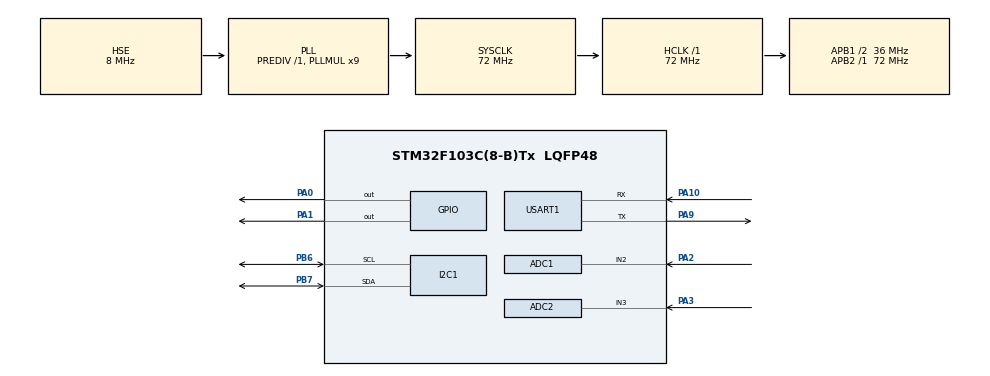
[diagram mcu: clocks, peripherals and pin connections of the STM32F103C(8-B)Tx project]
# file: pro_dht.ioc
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ADC1.Channel-0\#ChannelRegularConversion=ADC_CHANNEL_2
ADC1.NbrOfConversionFlag=1
ADC1.Rank-0\#ChannelRegularConversion=1
ADC1.SamplingTime-0\#ChannelRegularConversion=ADC_SAMPLETIME_55CYCLES_5
ADC1.master=1
ADC2.Channel-0\#ChannelRegularConversion=ADC_CHANNEL_3
ADC2.NbrOfConversionFlag=1
ADC2.Rank-0\#ChannelRegularConversion=1
ADC2.SamplingTime-0\#ChannelRegularConversion=ADC_SAMPLETIME_55CYCLES_5
FREERTOS.Queues01=myQueue01,16,uint16_t,0,Dynamic,NULL,NULL;myQueue02,16,uint16_t,0,Dynamic,NULL,NULL;myQueue03,16,uint16_t,0,Dynamic,NULL,NULL;myQueue04,16,uint16_t,0,Dynamic,NULL,NULL;myQueue05,16,uint16_t,0,Dynamic,NULL,NULL;myQueue06,16,uint16_t,0,Dynamic,NULL,NULL
FREERTOS.Tasks01=defaultTask,0,128,StartDefaultTask,Default,NULL,Dynamic,NULL,NULL;DHT11,0,128,DHT11_FULL,Default,NULL,Dynamic,NULL,NULL;Anh_Sang,0,128,Anh_Sang_FULL,Default,NULL,Dynamic,NULL,NULL
Mcu.Family=STM32F1
Mcu.Name=STM32F103C(8-B)Tx
Mcu.Package=LQFP48
NVIC.PriorityGroup=NVIC_PRIORITYGROUP_4
NVIC.USART1_IRQn=true\:5\:0\:false\:false\:true\:true\:true\:true\:true
PA0-WKUP.Signal=GPIO_Output
PA1.Signal=GPIO_Output
PA10.Mode=Asynchronous
PA10.Signal=USART1_RX
PA13.Mode=Serial_Wire
PA13.Signal=SYS_JTMS-SWDIO
PA14.Mode=Serial_Wire
PA14.Signal=SYS_JTCK-SWCLK
PA2.Signal=ADCx_IN2
PA3.Signal=ADCx_IN3
PA9.Mode=Asynchronous
PA9.Signal=USART1_TX
PB6.GPIO_Speed=GPIO_SPEED_FREQ_HIGH
PB6.Mode=I2C
PB6.Signal=I2C1_SCL
PB7.GPIO_Speed=GPIO_SPEED_FREQ_HIGH
PB7.Mode=I2C
PB7.Signal=I2C1_SDA
PD0-OSC_IN.Mode=HSE-External-Oscillator
PD0-OSC_IN.Signal=RCC_OSC_IN
PD1-OSC_OUT.Mode=HSE-External-Oscillator
PD1-OSC_OUT.Signal=RCC_OSC_OUT
ProjectManager.HeapSize=0x200
ProjectManager.StackSize=0x400
ProjectManager.TargetToolchain=MDK-ARM V5
RCC.ADCPresc=RCC_ADCPCLK2_DIV6
RCC.AHBFreq_Value=72000000
RCC.APB1CLKDivider=RCC_HCLK_DIV2
RCC.APB1Freq_Value=36000000
RCC.APB1TimFreq_Value=72000000
RCC.APB2Freq_Value=72000000
RCC.APB2TimFreq_Value=72000000
RCC.HCLKFreq_Value=72000000
RCC.PLLMUL=RCC_PLL_MUL9
RCC.PLLSourceVirtual=RCC_PLLSOURCE_HSE
RCC.SYSCLKFreq_VALUE=72000000
RCC.SYSCLKSource=RCC_SYSCLKSOURCE_PLLCLK
RCC.USBFreq_Value=72000000
SH.ADCx_IN2.0=ADC1_IN2,IN2
SH.ADCx_IN3.0=ADC2_IN3,IN3
TIM4.Period=0xffff-1
TIM4.Prescaler=72-1
USART1.VirtualMode=VM_ASYNC
VP_FREERTOS_VS_CMSIS_V1.Mode=CMSIS_V1
VP_TIM4_VS_ClockSourceINT.Mode=Internal
board=custom

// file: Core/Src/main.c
/* USER CODE BEGIN Header */
/**
  ******************************************************************************
  * @file           : main.c
  * @brief          : Main program body
  ******************************************************************************
  * @attention
  *
  * <h2><center>&copy; Copyright (c) 2021 STMicroelectronics.
  * All rights reserved.</center></h2>
  *
  * This software component is licensed by ST under BSD 3-Clause license,
  * the "License"; You may not use this file except in compliance with the
  * License. You may obtain a copy of the License at:
  *                        opensource.org/licenses/BSD-3-Clause
  *
  ******************************************************************************
  */
/* USER CODE END Header */
#include "main.h"
#include "cmsis_os.h"

/* USER CODE BEGIN Includes */

#include "i2c-lcd.h"
#include "stdio.h"
#include <string.h>
#include <stdlib.h>
/* USER CODE END Includes */

ADC_HandleTypeDef hadc1;
ADC_HandleTypeDef hadc2;

I2C_HandleTypeDef hi2c1;

TIM_HandleTypeDef htim4;

UART_HandleTypeDef huart1;

osThreadId defaultTaskHandle;
osThreadId DHT11Handle;
osThreadId Anh_SangHandle;
osThreadId LCDHandle;
/* USER CODE BEGIN PV */
osMessageQId myQueue01Handle;
osMessageQId myQueue02Handle;
osMessageQId myQueue03Handle;
osMessageQId myQueue04Handle;
osMessageQId myQueue05Handle;
osMessageQId myQueue06Handle;
/* USER CODE END PV */

void SystemClock_Config(void);
static void MX_GPIO_Init(void);
static void MX_I2C1_Init(void);
static void MX_TIM4_Init(void);
static void MX_ADC1_Init(void);
static void MX_ADC2_Init(void);
static void MX_USART1_UART_Init(void);
void StartDefaultTask(void const * argument);
void DHT11_FULL(void const * argument);
void Anh_Sang_FULL(void const * argument);
void LCD_FULL(void const * argument);
/* USER CODE BEGIN PFP */
uint32_t adc1_value = 0;
uint32_t adc2_value = 0;
#define MAX_BUFFER_SIZE 1024
/* USER CODE END PFP */

/* USER CODE BEGIN 0 */

//delay function in microseconds
void delay (uint16_t time)
{
	__HAL_TIM_SET_COUNTER(&htim4, 0);
	while ((__HAL_TIM_GET_COUNTER(&htim4))<time);
}

/*
//Finction to display temperature
void Display_Temp (int Temp)
{
	char str[20] = {0};
	lcd_put_cur(0,0);

	sprintf (str, "Temp:%d", Temp);
	lcd_send_string(str);
	lcd_send_data('C');
}

////function to display RH
void Display_Rh (int Rh)
{
	char str[20] = {0};
	lcd_put_cur(0,10);

	sprintf (str, "Rh:%d", Rh);
	lcd_send_string(str);
	lcd_send_data('%');
}
*/
//variables declarations
uint8_t Rh_byte1, Rh_byte2, Temp_byte1, Temp_byte2;
uint16_t SUM, RH, TEMP;

uint32_t Temperature = 0;
uint32_t Humidity = 0;
uint8_t Presence = 0;

//function to set the pins as outputs
void Set_Pin_Output(GPIO_TypeDef *GPIOx, uint16_t GPIO_Pin)
{
	GPIO_InitTypeDef GPIO_InitStruct = {0};
	GPIO_InitStruct.Pin = GPIO_Pin;
	GPIO_InitStruct.Mode = GPIO_MODE_OUTPUT_PP;
	GPIO_InitStruct.Speed = GPIO_SPEED_FREQ_LOW;
	HAL_GPIO_Init(GPIOx, &GPIO_InitStruct);
}

//function to set pin as input
void Set_Pin_Input(GPIO_TypeDef *GPIOx, uint16_t GPIO_Pin)
{
	GPIO_InitTypeDef GPIO_InitStruct = {0};
	GPIO_InitStruct.Pin = GPIO_Pin;
	GPIO_InitStruct.Mode = GPIO_MODE_INPUT;
	GPIO_InitStruct.Pull = GPIO_NOPULL; //can be changed to PULLUP if no data is received from the pin
	HAL_GPIO_Init(GPIOx, &GPIO_InitStruct);
}

/***************************DHT11 FUNCTIONS BEGIN HERE**********************************************/
//Define the pin and the port for DHT11 Sensor
#define DHT11_PORT GPIOA
#define DHT11_PIN GPIO_PIN_1

//Function to send the start signal
void DHT11_Start (void)
{
	Set_Pin_Output (DHT11_PORT, DHT11_PIN); //set the dht pin as output
	/***********************************************/
	HAL_GPIO_WritePin(DHT11_PORT, DHT11_PIN, 1); //initialize with data pin high
	HAL_Delay(1000); //wait for 1000 milliseconds
	/***********************************************/

	HAL_GPIO_WritePin (DHT11_PORT, DHT11_PIN, 0); //pull the pin low
	delay(18000); //wait 18 milliseconds
	HAL_GPIO_WritePin (DHT11_PORT, DHT11_PIN, 1); //pull the pin high
	delay(20); //wait for 20 microseconds
	Set_Pin_Input(DHT11_PORT, DHT11_PIN); //set the pin as input
}

//dh11 function to check response
uint8_t DHT11_Check_Response (void)
{
	uint8_t Response = 0;
	delay(40); //first wait for 40 microseconds
	if (!(HAL_GPIO_ReadPin (DHT11_PORT, DHT11_PIN))) //check for pin to be low
	{
		delay(80); //wait for 80 microseconds
		if((HAL_GPIO_ReadPin (DHT11_PORT, DHT11_PIN))) Response = 1; //check if pin is high and return 1 to show sensor is present
		else Response = -1; //255
	}
	while ((HAL_GPIO_ReadPin (DHT11_PORT, DHT11_PIN))); //wait for the pin to go low again

	return Response;
}

//function to read data from dht11 signal pin
uint8_t DHT11_Read (void)
{
	uint8_t i, j;
	for (j=0;j<8;j++)
	{
		while(!(HAL_GPIO_ReadPin (DHT11_PORT, DHT11_PIN))); //wait for the pin to change to high
		delay(40); //wait for 40 microseconds
		if (!(HAL_GPIO_ReadPin (DHT11_PORT, DHT11_PIN))) //if the pin is low
		{
			i&= ~(1<<(7-j)); //write 0
		}
		else i|= (1<<(7-j)); //if the pin is high write 1
		while ((HAL_GPIO_ReadPin (DHT11_PORT, DHT11_PIN))); //wait for the pin to go low
	}

	return i;
}
//////////////////////////////////////DHT0///////////////////////
/* USER CODE END 0
void Display_Temp5 (int Temp5)
{
	char str[20] = {0};
	lcd_put_cur(1,0);

	sprintf (str, "Temp:%d", Temp5);
	lcd_send_string(str);
	lcd_send_data('C');
}

//function to display RH
void Display_Rh5 (int Rh5)
{
	char str[20] = {0};
	lcd_put_cur(1,10);

	sprintf (str, "Rh:%d", Rh5);
	lcd_send_string(str);
	lcd_send_data('%');
}
*/
//variables declarations
uint8_t Rh5_byte1, Rh5_byte2, Temp5_byte1, Temp5_byte2;
uint16_t SUM5, RH5, TEMP5;

uint32_t Temperature5 = 0;
uint32_t Humidity5 = 0;
uint8_t Presence5 = 0;

//function to set the pins as outputs
void Set_Pin_Output5(GPIO_TypeDef *GPIOx, uint16_t GPIO_Pin)
{
	GPIO_InitTypeDef GPIO_InitStruct = {0};
	GPIO_InitStruct.Pin = GPIO_Pin;
	GPIO_InitStruct.Mode = GPIO_MODE_OUTPUT_PP;
	GPIO_InitStruct.Speed = GPIO_SPEED_FREQ_LOW;
	HAL_GPIO_Init(GPIOx, &GPIO_InitStruct);
}

//function to set pin as input
void Set_Pin_Input5(GPIO_TypeDef *GPIOx, uint16_t GPIO_Pin)
{
	GPIO_InitTypeDef GPIO_InitStruct = {0};
	GPIO_InitStruct.Pin = GPIO_Pin;
	GPIO_InitStruct.Mode = GPIO_MODE_INPUT;
	GPIO_InitStruct.Pull = GPIO_NOPULL; //can be changed to PULLUP if no data is received from the pin
	HAL_GPIO_Init(GPIOx, &GPIO_InitStruct);
}

/***************************DHT11 FUNCTIONS BEGIN HERE**********************************************/
//Define the pin and the port for DHT11 Sensor
#define DHT11_PORT GPIOA
#define DHT11_PIN5 GPIO_PIN_0

//Function to send the start signal
void DHT11_Start5 (void)
{
	Set_Pin_Output5 (DHT11_PORT, DHT11_PIN5); //set the dht pin as output
	/***********************************************/
	HAL_GPIO_WritePin(DHT11_PORT, DHT11_PIN5, 1); //initialize with data pin high
	HAL_Delay(1000); //wait for 1000 milliseconds
	/***********************************************/

	HAL_GPIO_WritePin (DHT11_PORT, DHT11_PIN5, 0); //pull the pin low
	delay(18000); //wait 18 milliseconds
	HAL_GPIO_WritePin (DHT11_PORT, DHT11_PIN5, 1); //pull the pin high
	delay(20); //wait for 20 microseconds
	Set_Pin_Input5(DHT11_PORT, DHT11_PIN5); //set the pin as input
}

//dh11 function to check response
uint8_t DHT11_Check_Response5 (void)
{
	uint8_t Response5 = 0;
	delay(40); //first wait for 40 microseconds
	if (!(HAL_GPIO_ReadPin (DHT11_PORT, DHT11_PIN5))) //check for pin to be low
	{
		delay(80); //wait for 80 microseconds
		if((HAL_GPIO_ReadPin (DHT11_PORT, DHT11_PIN5))) Response5 = 1; //check if pin is high and return 1 to show sensor is present
		else Response5 = -1; //255
	}
	while ((HAL_GPIO_ReadPin (DHT11_PORT, DHT11_PIN5))); //wait for the pin to go low again

	return Response5;
}

//function to read data from dht11 signal pin
uint8_t DHT11_Read5 (void)
{
	uint8_t i, j;
	for (j=0;j<8;j++)
	{
		while(!(HAL_GPIO_ReadPin (DHT11_PORT, DHT11_PIN5))); //wait for the pin to change to high
		delay(40); //wait for 40 microseconds
		if (!(HAL_GPIO_ReadPin (DHT11_PORT, DHT11_PIN5))) //if the pin is low
		{
			i&= ~(1<<(7-j)); //write 0
		}
		else i|= (1<<(7-j)); //if the pin is high write 1
		while ((HAL_GPIO_ReadPin (DHT11_PORT, DHT11_PIN5))); //wait for the pin to go low
	}

	return i;
}
////////////
char rxBuffer[3];
void HAL_UART_RxCpltCallback(UART_HandleTypeDef *huart)
{

  if(huart->Instance==USART1)
  {
    if(strcmp(rxBuffer, "O1") == 0)
    {
      HAL_GPIO_WritePin(GPIOA, GPIO_PIN_6, 1); // Turn on LED1
    }
    else if(strcmp(rxBuffer, "X1") == 0)
    {
      HAL_GPIO_WritePin(GPIOA, GPIO_PIN_6, 0); // Turn off LED1
    }
    if(strcmp(rxBuffer, "O2") == 0)
    {
      HAL_GPIO_WritePin(GPIOA, GPIO_PIN_7, 1); // Turn on LED2
    }
    else if(strcmp(rxBuffer, "X2") == 0)
    {
      HAL_GPIO_WritePin(GPIOA, GPIO_PIN_7, 0); // Turn off LED2
    }
    if(strcmp(rxBuffer, "O3") == 0)
    {
      HAL_GPIO_WritePin(GPIOA, GPIO_PIN_8, 1); // Turn on LED3
    }
    else if(strcmp(rxBuffer, "X3") == 0)
    {
      HAL_GPIO_WritePin(GPIOA, GPIO_PIN_8, 0); // Turn off LED3
    }
    HAL_UART_Receive_IT(&huart1, (uint8_t *)rxBuffer, 2); // Enable interrupt receive again
  }
}

int main(void)
{

  /* MCU Configuration--------------------------------------------------------*/

  /* Reset of all peripherals, Initializes the Flash interface and the Systick. */
  HAL_Init();

  /* Configure the system clock */
  SystemClock_Config();

  /* Initialize all configured peripherals */
  MX_GPIO_Init();
  MX_I2C1_Init();
  MX_TIM4_Init();
  MX_ADC1_Init();
  MX_ADC2_Init();
	MX_USART1_UART_Init();
  /* USER CODE BEGIN 2 */
//	HAL_UART_Receive_IT(&huart1, (uint8_t *)rxBuffer, 2);
	HAL_TIM_Base_Start(&htim4);

	lcd_init(); //initialize lcd
	lcd_send_string("INITIALIZING.."); //display string on lcd
	HAL_Delay(2000); //wait for 2 seconds
	lcd_clear(); //clear lcd display

  /* USER CODE END 2 */

	osMessageQDef(myQueue01, 16, uint16_t);
  myQueue01Handle = osMessageCreate(osMessageQ(myQueue01), NULL);

  /* definition and creation of myQueue02 */
  osMessageQDef(myQueue02, 16, uint16_t);
  myQueue02Handle = osMessageCreate(osMessageQ(myQueue02), NULL);

  /* definition and creation of myQueue03 */
  osMessageQDef(myQueue03, 16, uint16_t);
  myQueue03Handle = osMessageCreate(osMessageQ(myQueue03), NULL);

  /* definition and creation of myQueue04 */
  osMessageQDef(myQueue04, 16, uint16_t);
  myQueue04Handle = osMessageCreate(osMessageQ(myQueue04), NULL);
	/* definition and creation of myQueue05 */
  osMessageQDef(myQueue05, 16, uint16_t);
  myQueue05Handle = osMessageCreate(osMessageQ(myQueue05), NULL);

  /* definition and creation of myQueue06 */
  osMessageQDef(myQueue06, 16, uint16_t);
  myQueue06Handle = osMessageCreate(osMessageQ(myQueue06), NULL);
  /* Create the thread(s) */
  /* definition and creation of defaultTask */
  osThreadDef(defaultTask, StartDefaultTask, osPriorityNormal, 0, 128);
  defaultTaskHandle = osThreadCreate(osThread(defaultTask), NULL);

  /* definition and creation of DHT11 */
  osThreadDef(DHT11, DHT11_FULL, osPriorityNormal, 0, 128);
  DHT11Handle = osThreadCreate(osThread(DHT11), NULL);
	/* definition and creation of Anh_Sang */
  osThreadDef(Anh_Sang, Anh_Sang_FULL, osPriorityNormal, 0, 128);
  Anh_SangHandle = osThreadCreate(osThread(Anh_Sang), NULL);
	/* definition and creation of LCD */
  osThreadDef(LCD, LCD_FULL, osPriorityNormal, 0, 128);
  LCDHandle = osThreadCreate(osThread(LCD), NULL);

  /* Start scheduler */
  osKernelStart();
  /* We should never get here as control is now taken by the scheduler */
  /* Infinite loop */
  while (1)
  {
			HAL_GPIO_WritePin(GPIOA,GPIO_PIN_11,1);
//			HAL_UART_Transmit(&huart1, "Hello" ,6,10);
//			HAL_Delay(500);
  }
}

void SystemClock_Config(void)
{
  RCC_OscInitTypeDef RCC_OscInitStruct = {0};
  RCC_ClkInitTypeDef RCC_ClkInitStruct = {0};

  /** Initializes the RCC Oscillators according to the specified parameters
  * in the RCC_OscInitTypeDef structure.
  */
  RCC_OscInitStruct.OscillatorType = RCC_OSCILLATORTYPE_HSE;
  RCC_OscInitStruct.HSEState = RCC_HSE_ON;
  RCC_OscInitStruct.HSEPredivValue = RCC_HSE_PREDIV_DIV1;
  RCC_OscInitStruct.HSIState = RCC_HSI_ON;
  RCC_OscInitStruct.PLL.PLLState = RCC_PLL_ON;
  RCC_OscInitStruct.PLL.PLLSource = RCC_PLLSOURCE_HSE;
  RCC_OscInitStruct.PLL.PLLMUL = RCC_PLL_MUL9;
  if (HAL_RCC_OscConfig(&RCC_OscInitStruct) != HAL_OK)
  {
    Error_Handler();
  }

  /** Initializes the CPU, AHB and APB buses clocks
  */
  RCC_ClkInitStruct.ClockType = RCC_CLOCKTYPE_HCLK|RCC_CLOCKTYPE_SYSCLK
                              |RCC_CLOCKTYPE_PCLK1|RCC_CLOCKTYPE_PCLK2;
  RCC_ClkInitStruct.SYSCLKSource = RCC_SYSCLKSOURCE_PLLCLK;
  RCC_ClkInitStruct.AHBCLKDivider = RCC_SYSCLK_DIV1;
  RCC_ClkInitStruct.APB1CLKDivider = RCC_HCLK_DIV2;
  RCC_ClkInitStruct.APB2CLKDivider = RCC_HCLK_DIV1;

  if (HAL_RCC_ClockConfig(&RCC_ClkInitStruct, FLASH_LATENCY_2) != HAL_OK)
  {
    Error_Handler();
  }

}

static void MX_ADC1_Init(void)
{

  ADC_ChannelConfTypeDef sConfig = {0};

  /** Common config
  */
  hadc1.Instance = ADC1;
  hadc1.Init.ScanConvMode = ADC_SCAN_DISABLE;
  hadc1.Init.ContinuousConvMode = DISABLE;
  hadc1.Init.DiscontinuousConvMode = DISABLE;
  hadc1.Init.ExternalTrigConv = ADC_SOFTWARE_START;
  hadc1.Init.DataAlign = ADC_DATAALIGN_RIGHT;
  hadc1.Init.NbrOfConversion = 1;
  if (HAL_ADC_Init(&hadc1) != HAL_OK)
  {
    Error_Handler();
  }

  /** Configure Regular Channel
  */
  sConfig.Channel = ADC_CHANNEL_2;
  sConfig.Rank = ADC_REGULAR_RANK_1;
  sConfig.SamplingTime = ADC_SAMPLETIME_55CYCLES_5;
  if (HAL_ADC_ConfigChannel(&hadc1, &sConfig) != HAL_OK)
  {
    Error_Handler();
  }

}

static void MX_ADC2_Init(void)
{

  ADC_ChannelConfTypeDef sConfig = {0};

  /** Common config
  */
  hadc2.Instance = ADC2;
  hadc2.Init.ScanConvMode = ADC_SCAN_DISABLE;
  hadc2.Init.ContinuousConvMode = DISABLE;
  hadc2.Init.DiscontinuousConvMode = DISABLE;
  hadc2.Init.ExternalTrigConv = ADC_SOFTWARE_START;
  hadc2.Init.DataAlign = ADC_DATAALIGN_RIGHT;
  hadc2.Init.NbrOfConversion = 1;
  if (HAL_ADC_Init(&hadc2) != HAL_OK)
  {
    Error_Handler();
  }

  /** Configure Regular Channel
  */
  sConfig.Channel = ADC_CHANNEL_3;
  sConfig.Rank = ADC_REGULAR_RANK_1;
  sConfig.SamplingTime = ADC_SAMPLETIME_55CYCLES_5;
  if (HAL_ADC_ConfigChannel(&hadc2, &sConfig) != HAL_OK)
  {
    Error_Handler();
  }

}

static void MX_I2C1_Init(void)
{

  hi2c1.Instance = I2C1;
  hi2c1.Init.ClockSpeed = 100000;
  hi2c1.Init.DutyCycle = I2C_DUTYCYCLE_2;
  hi2c1.Init.OwnAddress1 = 0;
  hi2c1.Init.AddressingMode = I2C_ADDRESSINGMODE_7BIT;
  hi2c1.Init.DualAddressMode = I2C_DUALADDRESS_DISABLE;
  hi2c1.Init.OwnAddress2 = 0;
  hi2c1.Init.GeneralCallMode = I2C_GENERALCALL_DISABLE;
  hi2c1.Init.NoStretchMode = I2C_NOSTRETCH_DISABLE;
  if (HAL_I2C_Init(&hi2c1) != HAL_OK)
  {
    Error_Handler();
  }

}

static void MX_TIM4_Init(void)
{

  TIM_ClockConfigTypeDef sClockSourceConfig = {0};
  TIM_MasterConfigTypeDef sMasterConfig = {0};

  htim4.Instance = TIM4;
  htim4.Init.Prescaler = 72-1;
  htim4.Init.CounterMode = TIM_COUNTERMODE_UP;
  htim4.Init.Period = 0xffff-1;
  htim4.Init.ClockDivision = TIM_CLOCKDIVISION_DIV1;
  htim4.Init.AutoReloadPreload = TIM_AUTORELOAD_PRELOAD_DISABLE;
  if (HAL_TIM_Base_Init(&htim4) != HAL_OK)
  {
    Error_Handler();
  }
  sClockSourceConfig.ClockSource = TIM_CLOCKSOURCE_INTERNAL;
  if (HAL_TIM_ConfigClockSource(&htim4, &sClockSourceConfig) != HAL_OK)
  {
    Error_Handler();
  }
  sMasterConfig.MasterOutputTrigger = TIM_TRGO_RESET;
  sMasterConfig.MasterSlaveMode = TIM_MASTERSLAVEMODE_DISABLE;
  if (HAL_TIMEx_MasterConfigSynchronization(&htim4, &sMasterConfig) != HAL_OK)
  {
    Error_Handler();
  }

}
static void MX_USART1_UART_Init(void)
{

  huart1.Instance = USART1;
  huart1.Init.BaudRate = 9600;
  huart1.Init.WordLength = UART_WORDLENGTH_8B;
  huart1.Init.StopBits = UART_STOPBITS_1;
  huart1.Init.Parity = UART_PARITY_NONE;
  huart1.Init.Mode = UART_MODE_TX_RX;
  huart1.Init.HwFlowCtl = UART_HWCONTROL_NONE;
  huart1.Init.OverSampling = UART_OVERSAMPLING_16;
  if (HAL_UART_Init(&huart1) != HAL_OK)
  {
    Error_Handler();
  }

}

static void MX_GPIO_Init(void)
{
  GPIO_InitTypeDef GPIO_InitStruct = {0};

  /* GPIO Ports Clock Enable */
  __HAL_RCC_GPIOD_CLK_ENABLE();
  __HAL_RCC_GPIOA_CLK_ENABLE();
  __HAL_RCC_GPIOB_CLK_ENABLE();

  /*Configure GPIO pin Output Level */
  //HAL_GPIO_WritePin(GPIOA, GPIO_PIN_1, GPIO_PIN_RESET);
	HAL_GPIO_WritePin(GPIOA, GPIO_PIN_1, 1);
	HAL_GPIO_WritePin(GPIOA, GPIO_PIN_4, GPIO_PIN_RESET);
	HAL_GPIO_WritePin(GPIOA, GPIO_PIN_5, GPIO_PIN_RESET);
	HAL_GPIO_WritePin(GPIOA, GPIO_PIN_6, GPIO_PIN_RESET);
	HAL_GPIO_WritePin(GPIOA, GPIO_PIN_7, GPIO_PIN_RESET);
	HAL_GPIO_WritePin(GPIOA, GPIO_PIN_8, GPIO_PIN_RESET);
	HAL_GPIO_WritePin(GPIOA, GPIO_PIN_11, GPIO_PIN_RESET);
  /*Configure GPIO pin : PA1 */
  GPIO_InitStruct.Pin = GPIO_PIN_1 | GPIO_PIN_4  | GPIO_PIN_5 | GPIO_PIN_6 | GPIO_PIN_7 | GPIO_PIN_8 | GPIO_PIN_11;
  GPIO_InitStruct.Mode = GPIO_MODE_OUTPUT_PP;
  GPIO_InitStruct.Pull = GPIO_NOPULL;
  GPIO_InitStruct.Speed = GPIO_SPEED_FREQ_LOW;
  HAL_GPIO_Init(GPIOA, &GPIO_InitStruct);

}

void StartDefaultTask(void const * argument)
{
  /* USER CODE BEGIN 5 */
		lcd_init();
  /* Infinite loop */
  for(;;)
  {

	xQueueReceive(myQueue01Handle, &adc1_value, portMAX_DELAY);
	xQueueReceive(myQueue02Handle, &adc2_value, portMAX_DELAY);
	xQueueReceive(myQueue03Handle, &Temperature, portMAX_DELAY);
	xQueueReceive(myQueue04Handle, &Humidity, portMAX_DELAY);
	xQueueReceive(myQueue05Handle, &Temperature5, portMAX_DELAY);
	xQueueReceive(myQueue06Handle, &Humidity5, portMAX_DELAY);

	char str[20];
	lcd_put_cur(0,0);
	sprintf(str, "L:%d", adc1_value);
	lcd_send_string(str);
	lcd_send_string("Lux");

	lcd_put_cur(0,10);
	sprintf(str, "L:%d", adc2_value);
	lcd_send_string(str);
	lcd_send_string("Lux");

	lcd_put_cur(1,0);		// chia côt hàng
	sprintf (str, "Temp:%d", Temperature);
	lcd_send_string(str);
	lcd_send_data('C');

	lcd_put_cur(1,10);
	sprintf (str, "Rh:%d", Humidity);
	lcd_send_string(str);
	lcd_send_data('%');

	lcd_put_cur(2,0);
	sprintf (str, "Temp:%d", Temperature5);
	lcd_send_string(str);
	lcd_send_data('C');

	lcd_put_cur(2,10);
	sprintf (str, "Rh:%d", Humidity5);
	lcd_send_string(str);
	lcd_send_data('%');

	osDelay(1);
  }
  /* USER CODE END 5 */
}

void DHT11_FULL(void const * argument)
{

  for(;;)
  {
		//Display_Temp(Temperature);
		//Display_Rh(Humidity);

		DHT11_Start();
		Presence = DHT11_Check_Response();

		Rh_byte1 = DHT11_Read ();
		Rh_byte2 = DHT11_Read ();
		Temp_byte1 = DHT11_Read ();
		Temp_byte2 = DHT11_Read ();
		SUM = DHT11_Read ();

		TEMP = Temp_byte1;
		RH = Rh_byte1;

		Temperature = (float) TEMP;
		Humidity = (float) RH;

		//Display_Temp5(Temperature5);
		//Display_Rh5(Humidity5);

		DHT11_Start5();
		Presence5 = DHT11_Check_Response5(); //record the response from the sensor

		//Five bytes of data
		Rh5_byte1 = DHT11_Read5 ();
		Rh5_byte2 = DHT11_Read5 ();
		Temp5_byte1 = DHT11_Read5 ();
		Temp5_byte2 = DHT11_Read5 ();
		SUM5 = DHT11_Read5 ();

		TEMP5 = Temp5_byte1;
		RH5 = Rh5_byte1;

		Temperature5 = (float) TEMP5;
		Humidity5 = (float) RH5;

		xQueueSend(myQueue03Handle, &Temperature, portMAX_DELAY);
		xQueueSend(myQueue04Handle, &Humidity, portMAX_DELAY);
		xQueueSend(myQueue05Handle, &Temperature5, portMAX_DELAY);
		xQueueSend(myQueue06Handle, &Humidity5, portMAX_DELAY);

		char *buffer1 = (char *)malloc(sizeof(char) * MAX_BUFFER_SIZE);
		if(buffer1 !=NULL){
			sprintf(buffer1, "\n\r %d  \r\n", Temperature);
//			HAL_UART_Transmit(&huart1, (uint8_t *)"AT+CIPSEND\r\n", strlen("AT+CIPSEND\r\n"), 100);
			while (HAL_UART_Receive(&huart1, (unsigned char *)buffer1, 2,100) !=HAL_OK ){}
			HAL_UART_Transmit(&huart1, (uint8_t *)buffer1, strlen(buffer1), 1000);
//			HAL_UART_Transmit(&huart1, (uint8_t *)"AT+CIPSEND\r\n", strlen("AT+CIPSEND\r\n"), 100);
			free(buffer1);
		}

		if (Temperature > 30)
        {
            HAL_GPIO_WritePin(GPIOA, GPIO_PIN_11, GPIO_PIN_SET);
        }
        else
        {
            HAL_GPIO_WritePin(GPIOA, GPIO_PIN_11, GPIO_PIN_RESET);
        }

    osDelay(1);
  }
  /* USER CODE END DHT11_FULL */
}
void Anh_Sang_FULL(void const * argument)
{
  for(;;)
  {
		HAL_ADC_Start(&hadc1);
		//HAL_ADC_PollForConversion(&hadc1, HAL_MAX_DELAY);
		adc1_value = HAL_ADC_GetValue(&hadc1);
		//HAL_Delay(300);

		HAL_ADC_Start(&hadc2);
		//HAL_ADC_PollForConversion(&hadc2, HAL_MAX_DELAY);
		adc2_value = HAL_ADC_GetValue(&hadc2);
		//HAL_Delay(300);

		xQueueSend(myQueue01Handle, &adc1_value, portMAX_DELAY);
		xQueueSend(myQueue02Handle, &adc2_value, portMAX_DELAY);
		 if (adc1_value > 1000)
        {
            HAL_GPIO_WritePin(GPIOA, GPIO_PIN_4, GPIO_PIN_SET);
        }
        else
        {
            HAL_GPIO_WritePin(GPIOA, GPIO_PIN_4, GPIO_PIN_RESET);
        }

		if (adc2_value > 1000)
        {
            HAL_GPIO_WritePin(GPIOA, GPIO_PIN_5, GPIO_PIN_SET);
        }
        else
        {
            HAL_GPIO_WritePin(GPIOA, GPIO_PIN_5, GPIO_PIN_RESET);
        }
    osDelay(1);
  }

}

////////
void LCD_FULL(void const * argument)
{
	//lcd_init();
  for(;;)
  {

  osDelay(1);
  }

}
void Error_Handler(void)
{
  __disable_irq();
  while (1)
  {
  }
}
